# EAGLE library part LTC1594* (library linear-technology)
4-Channel, Micropower Sampling 12-Bit Serial I/O A/D Converter

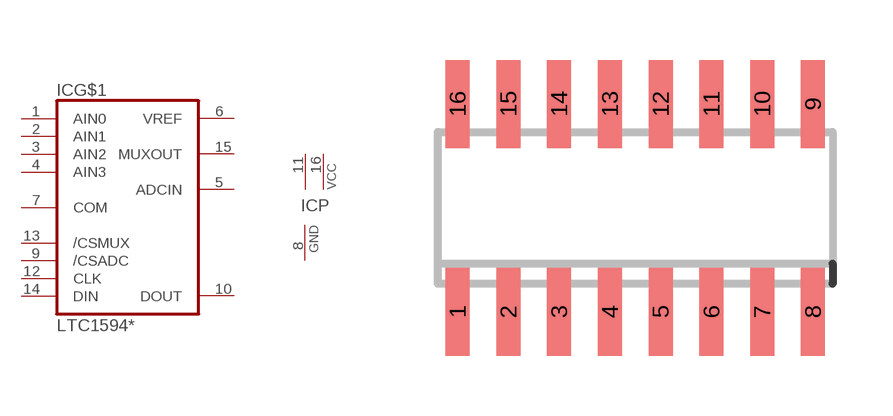
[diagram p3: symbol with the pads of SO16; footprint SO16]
Designator prefix IC; gates G$1=LTC1594 P=PWRN-CC-G

## LTC1594CS, LTC1594IS  [SO16]
1  G$1:AIN0  in
2  G$1:AIN1  in
3  G$1:AIN2  in
4  G$1:AIN3  in
5  G$1:ADCIN  in
6  G$1:VREF  in
7  G$1:COM  in
8  P:GND  pwr
9  G$1:/CSADC  in
10  G$1:DOUT  hiz
11  P:VCC  pwr
12  G$1:CLK  in
13  G$1:/CSMUX  in
14  G$1:DIN  in
15  G$1:MUXOUT  out
16  P:VCC  pwr

## Footprint SO16 (pad centres in mm)
smd 0.6 x 2.2: 1 -4.445,-2.6; 2 -3.175,-2.6; 3 -1.905,-2.6; 4 -0.635,-2.6; 5 0.635,-2.6; 6 1.905,-2.6; 7 3.175,-2.6; 8 4.445,-2.6; 9 4.445,2.6; 10 3.175,2.6; 11 1.905,2.6; 12 0.635,2.6; 13 -0.635,2.6; 14 -1.905,2.6; 15 -3.175,2.6; 16 -4.445,2.6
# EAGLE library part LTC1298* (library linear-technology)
Micropower, Sampling 12Bit A/D Converter Two Singleended Inputs

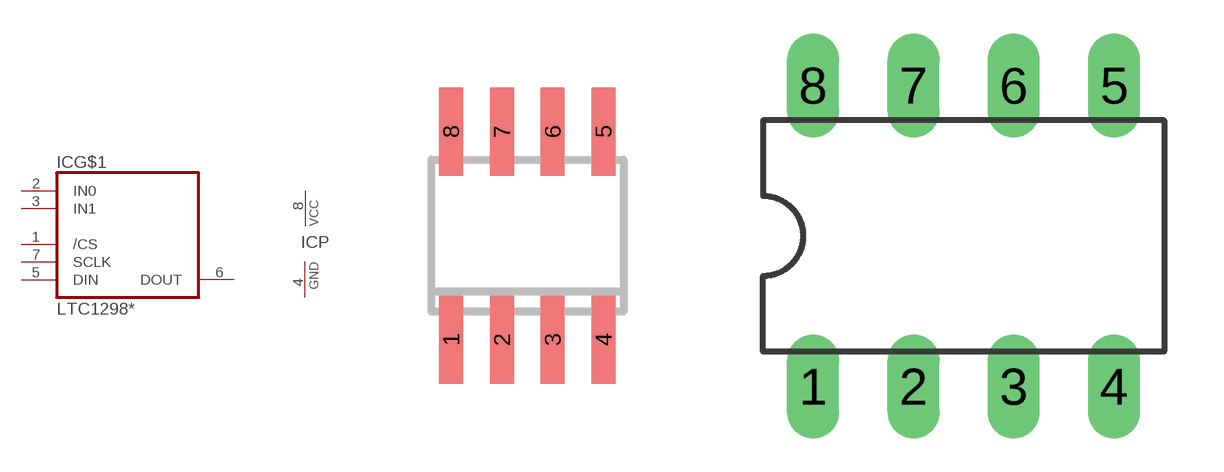
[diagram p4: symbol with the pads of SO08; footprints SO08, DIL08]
Designator prefix IC; gates G$1=LTC1298 P=PWRN-C-G

## LTC1298CS8, LTC1298IS8  [SO08]
1  G$1:/CS  in
2  G$1:IN0  in
3  G$1:IN1  in
4  P:GND  pwr
5  G$1:DIN  in
6  G$1:DOUT  hiz
7  G$1:SCLK  in
8  P:VCC  pwr

## LTC1298CN8, LTC1298IN8  [DIL08]
Pads as for SO08

## Footprint SO08 (pad centres in mm)
Small Outline IC
smd 0.6 x 2.2: 1 -1.905,-2.6; 2 -0.635,-2.6; 3 0.635,-2.6; 4 1.905,-2.6; 5 1.905,2.6; 6 0.635,2.6; 7 -0.635,2.6; 8 -1.905,2.6

## Footprint DIL08 (pad centres in mm)
Dual In Line Package
drill 0.813 long: 1 -3.81,-3.81; 2 -1.27,-3.81; 3 1.27,-3.81; 4 3.81,-3.81; 5 3.81,3.81; 6 1.27,3.81; 7 -1.27,3.81; 8 -3.81,3.81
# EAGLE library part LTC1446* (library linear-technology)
Dual 12-Bit Rail-to-Rail Micropower DACs

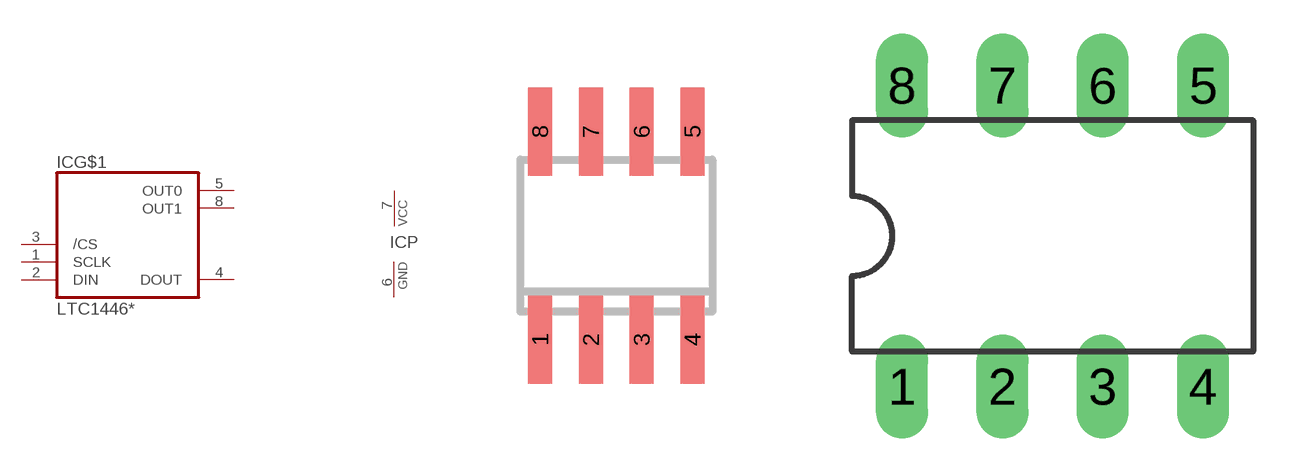
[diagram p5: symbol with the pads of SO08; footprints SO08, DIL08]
Designator prefix IC; gates G$1=LTC1446 P=PWRN-C-G

## LTC1446CS8, LTC1446IS8, LTC1446LCS8, LTC1446LIS8  [SO08]
1  G$1:SCLK  in
2  G$1:DIN  in
3  G$1:/CS  in
4  G$1:DOUT  hiz
5  G$1:OUT0  out
6  P:GND  pwr
7  P:VCC  pwr
8  G$1:OUT1  out

## LTC1446CN8, LTC1446IN8, LTC1446LCN8, LTC1446LIN8  [DIL08]
Pads as for SO08

## Footprint SO08 (pad centres in mm)
Small Outline IC
smd 0.6 x 2.2: 1 -1.905,-2.6; 2 -0.635,-2.6; 3 0.635,-2.6; 4 1.905,-2.6; 5 1.905,2.6; 6 0.635,2.6; 7 -0.635,2.6; 8 -1.905,2.6

## Footprint DIL08 (pad centres in mm)
Dual In Line Package
drill 0.813 long: 1 -3.81,-3.81; 2 -1.27,-3.81; 3 1.27,-3.81; 4 3.81,-3.81; 5 3.81,3.81; 6 1.27,3.81; 7 -1.27,3.81; 8 -3.81,3.81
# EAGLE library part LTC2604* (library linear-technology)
Quad 16-Bit Rail-to-Rail DACs

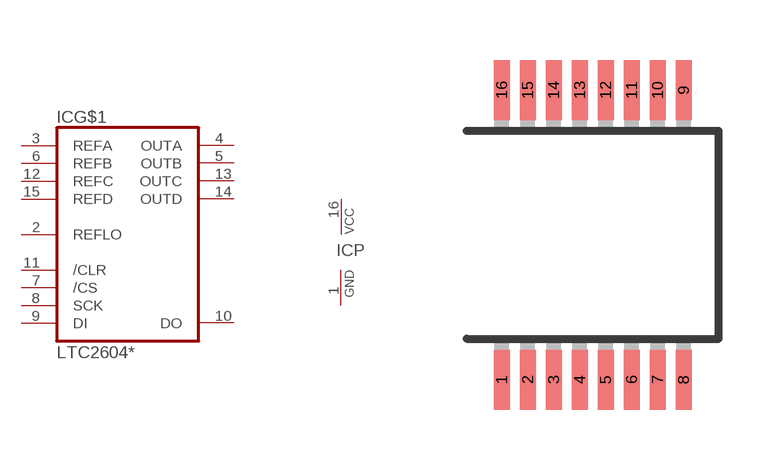
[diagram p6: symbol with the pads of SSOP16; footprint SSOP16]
Designator prefix IC; gates P=PWRN-C-G G$1=LTC2604

## LTC2604CGN, LTC2604IGN  [SSOP16]
1  P:GND  pwr
2  G$1:REFLO  pas
3  G$1:REFA  pas
4  G$1:OUTA  out
5  G$1:OUTB  out
6  G$1:REFB  pas
7  G$1:/CS  in
8  G$1:SCK  in
9  G$1:DI  in
10  G$1:DO  hiz
11  G$1:/CLR  in
12  G$1:REFC  pas
13  G$1:OUTC  out
14  G$1:OUTD  out
15  G$1:REFD  pas
16  P:VCC  pwr

## Footprint SSOP16 (pad centres in mm)
smd 0.4 x 1.5: 1 -2.275,-3.625; 2 -1.625,-3.625; 3 -0.975,-3.625; 4 -0.325,-3.625; 5 0.325,-3.625; 6 0.975,-3.625; 7 1.625,-3.625; 8 2.275,-3.625; 9 2.275,3.625; 10 1.625,3.625; 11 0.975,3.625; 12 0.325,3.625; 13 -0.325,3.625; 14 -0.975,3.625; 15 -1.625,3.625; 16 -2.275,3.625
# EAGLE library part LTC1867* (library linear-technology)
12-/16-Bit, 8-Channel 200ksps ADC

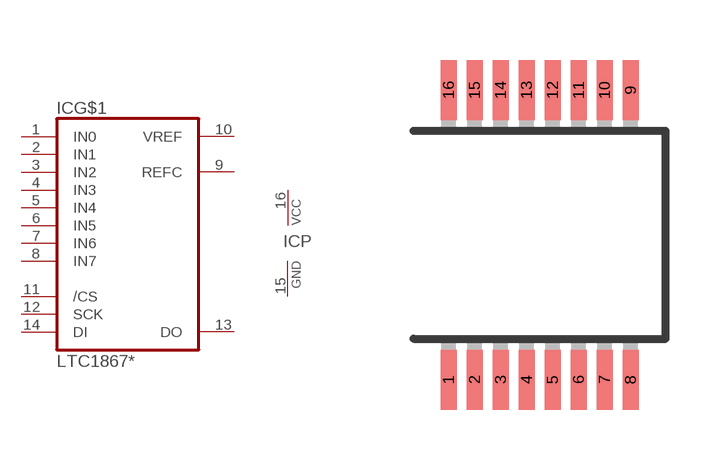
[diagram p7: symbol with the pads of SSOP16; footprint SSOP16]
Designator prefix IC; gates P=PWRN-C-G G$1=LTC1867

## LTC1867ACGN, LTC1867AIGN, LTC1867CGN, LTC1867IGN  [SSOP16]
1  G$1:IN0  in
2  G$1:IN1  in
3  G$1:IN2  in
4  G$1:IN3  in
5  G$1:IN4  in
6  G$1:IN5  in
7  G$1:IN6  in
8  G$1:IN7  in
9  G$1:REFC  pas
10  G$1:VREF  pas
11  G$1:/CS  in
12  G$1:SCK  in
13  G$1:DO  hiz
14  G$1:DI  in
15  P:GND  pwr
16  P:VCC  pwr

## Footprint SSOP16 (pad centres in mm)
smd 0.4 x 1.5: 1 -2.275,-3.625; 2 -1.625,-3.625; 3 -0.975,-3.625; 4 -0.325,-3.625; 5 0.325,-3.625; 6 0.975,-3.625; 7 1.625,-3.625; 8 2.275,-3.625; 9 2.275,3.625; 10 1.625,3.625; 11 0.975,3.625; 12 0.325,3.625; 13 -0.325,3.625; 14 -0.975,3.625; 15 -1.625,3.625; 16 -2.275,3.625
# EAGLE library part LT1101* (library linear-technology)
Precision, Micropower, Single Supply Instrumentation Amplifier (Fixed Gain A=10 or 100)

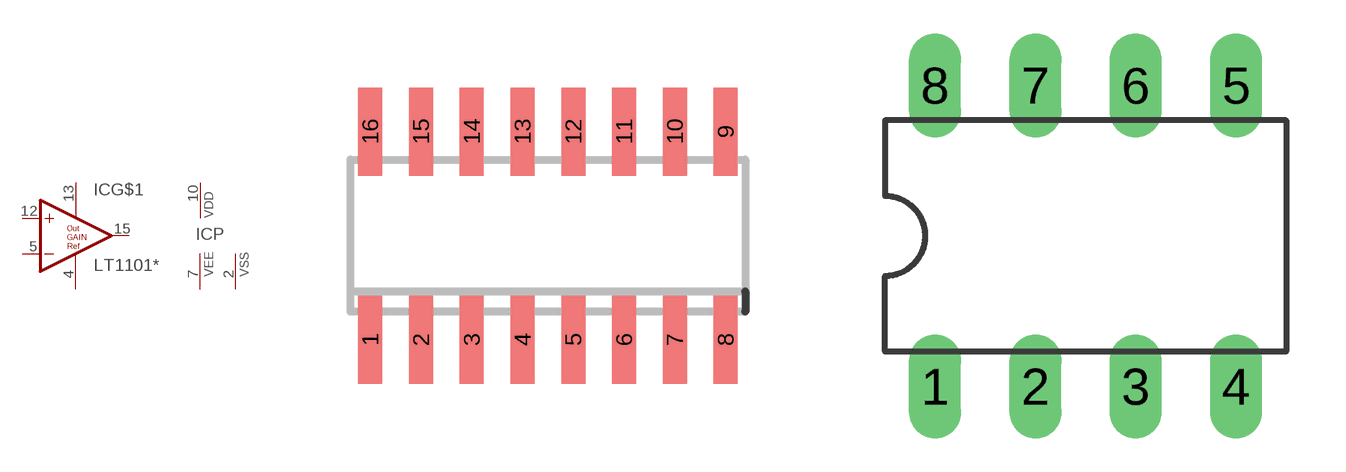
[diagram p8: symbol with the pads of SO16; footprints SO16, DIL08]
Designator prefix IC; gates G$1=LT1101 P=PWRN-D-E-S

## LT1101SW, LT1101ISW  [SO16]
2  P:VSS  pwr
4  G$1:GREF  pas
5  G$1:-IN  in
7  P:VEE  pwr
10  P:VDD  pwr
12  G$1:+IN  in
13  G$1:GOUT  pas
15  G$1:OUT  out

## LT1101ACN8, LT1101AIN8, LT1101CN8, LT1101IN8  [DIL08]
1  P:VSS  pwr
2  G$1:GREF  pas
3  G$1:-IN  in
4  P:VEE  pwr
5  P:VDD  pwr
6  G$1:+IN  in
7  G$1:GOUT  pas
8  G$1:OUT  out

## Footprint SO16 (pad centres in mm)
smd 0.6 x 2.2: 1 -4.445,-2.6; 2 -3.175,-2.6; 3 -1.905,-2.6; 4 -0.635,-2.6; 5 0.635,-2.6; 6 1.905,-2.6; 7 3.175,-2.6; 8 4.445,-2.6; 9 4.445,2.6; 10 3.175,2.6; 11 1.905,2.6; 12 0.635,2.6; 13 -0.635,2.6; 14 -1.905,2.6; 15 -3.175,2.6; 16 -4.445,2.6

## Footprint DIL08 (pad centres in mm)
Dual In Line Package
drill 0.813 long: 1 -3.81,-3.81; 2 -1.27,-3.81; 3 1.27,-3.81; 4 3.81,-3.81; 5 3.81,3.81; 6 1.27,3.81; 7 -1.27,3.81; 8 -3.81,3.81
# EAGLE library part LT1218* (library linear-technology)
Precision Rail-to-Rail Input and Output OpAmp with Shutdown Input

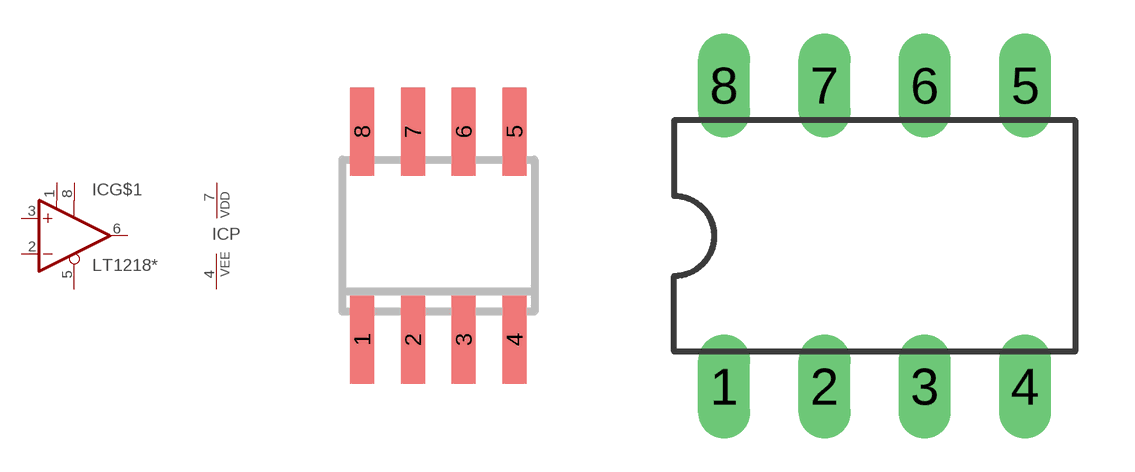
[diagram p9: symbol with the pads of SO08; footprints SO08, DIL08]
Designator prefix IC; gates G$1=LT1218 P=PWRN-D-E

## LT1218CS8, LT1218LCS8  [SO08]
1  G$1:TRIM1  pas
2  G$1:-IN  in
3  G$1:+IN  in
4  P:VEE  pwr
5  G$1:/SHDN  pas
6  G$1:OUT  out
7  P:VDD  pwr
8  G$1:TRIM2  pas

## LT1218CN8, LT1218LCN8  [DIL08]
Pads as for SO08

## Footprint SO08 (pad centres in mm)
Small Outline IC
smd 0.6 x 2.2: 1 -1.905,-2.6; 2 -0.635,-2.6; 3 0.635,-2.6; 4 1.905,-2.6; 5 1.905,2.6; 6 0.635,2.6; 7 -0.635,2.6; 8 -1.905,2.6

## Footprint DIL08 (pad centres in mm)
Dual In Line Package
drill 0.813 long: 1 -3.81,-3.81; 2 -1.27,-3.81; 3 1.27,-3.81; 4 3.81,-3.81; 5 3.81,3.81; 6 1.27,3.81; 7 -1.27,3.81; 8 -3.81,3.81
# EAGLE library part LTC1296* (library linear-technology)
Single Chip 12-Bit Data Acquisition System

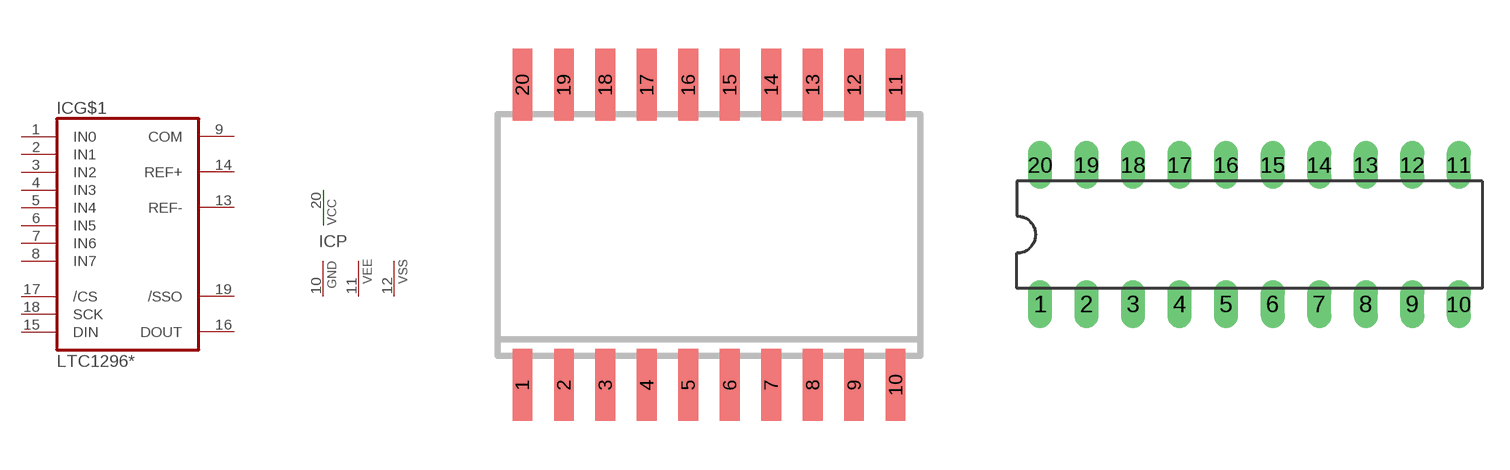
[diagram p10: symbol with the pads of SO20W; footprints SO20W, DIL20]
Designator prefix IC; gates G$1=LTC1296 P=PWRN-C-G-E-S

## LTC1296BCS, LTC1296CCS, LTC1296DCS  [SO20W]
1  G$1:IN0  in
2  G$1:IN1  in
3  G$1:IN2  in
4  G$1:IN3  in
5  G$1:IN4  in
6  G$1:IN5  in
7  G$1:IN6  in
8  G$1:IN7  in
9  G$1:COM  pas
10  P:GND  pwr
11  P:VEE  pwr
12  P:VSS  pwr
13  G$1:REF-  pas
14  G$1:REF+  pas
15  G$1:DIN  in
16  G$1:DOUT  hiz
17  G$1:/CS  in
18  G$1:SCK  in
19  G$1:/SSO  out
20  P:VCC  pwr

## LTC1296BCN, LTC1296BIN, LTC1296CCN, LTC1296CIN, LTC1296DCN, LTC1296DIN  [DIL20]
Pads as for SO20W

## Footprint SO20W (pad centres in mm)
smd 0.6 x 2.2: 1 -5.715,-4.6; 2 -4.445,-4.6; 3 -3.175,-4.6; 4 -1.905,-4.6; 5 -0.635,-4.6; 6 0.635,-4.6; 7 1.905,-4.6; 8 3.175,-4.6; 9 4.445,-4.6; 10 5.715,-4.6; 11 5.715,4.6; 12 4.445,4.6; 13 3.175,4.6; 14 1.905,4.6; 15 0.635,4.6; 16 -0.635,4.6; 17 -1.905,4.6; 18 -3.175,4.6; 19 -4.445,4.6; 20 -5.715,4.6

## Footprint DIL20 (pad centres in mm)
drill 0.813 long: 1 -11.43,-3.81; 2 -8.89,-3.81; 3 -6.35,-3.81; 4 -3.81,-3.81; 5 -1.27,-3.81; 6 1.27,-3.81; 7 3.81,-3.81; 8 6.35,-3.81; 9 8.89,-3.81; 10 11.43,-3.81; 11 11.43,3.81; 12 8.89,3.81; 13 6.35,3.81; 14 3.81,3.81; 15 1.27,3.81; 16 -1.27,3.81; 17 -3.81,3.81; 18 -6.35,3.81; 19 -8.89,3.81; 20 -11.43,3.81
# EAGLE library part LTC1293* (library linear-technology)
Single Chip 12-Bit Data Acquisition System

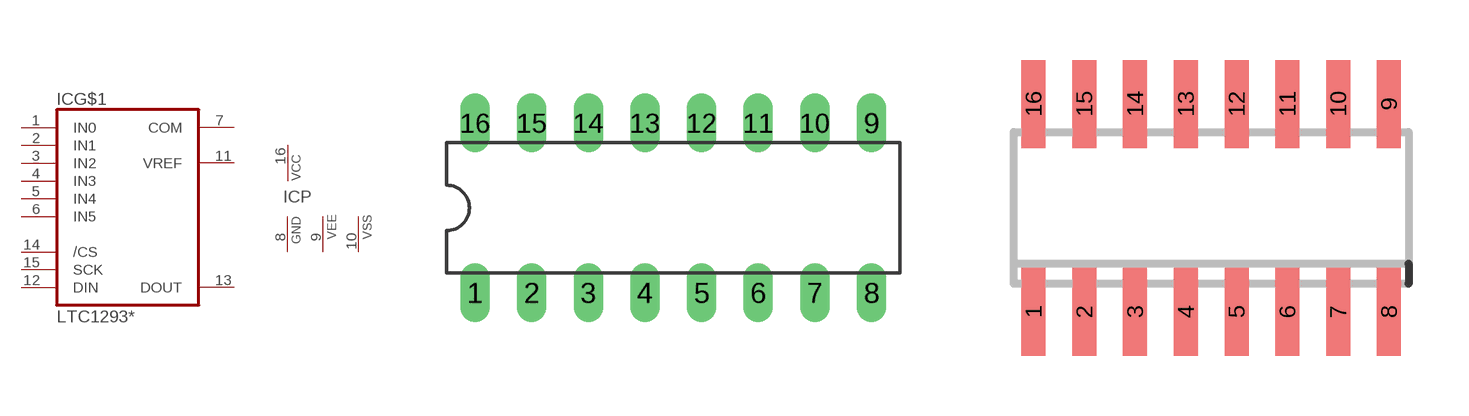
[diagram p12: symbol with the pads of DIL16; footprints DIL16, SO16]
Designator prefix IC; gates G$1=LTC1293 P=PWRN-C-G-E-S

## LTC1293BCN, LTC1293BIN, LTC1293CCN, LTC1293CIN, LTC1293DCN, LTC1293DIN  [DIL16]
1  G$1:IN0  in
2  G$1:IN1  in
3  G$1:IN2  in
4  G$1:IN3  in
5  G$1:IN4  in
6  G$1:IN5  in
7  G$1:COM  pas
8  P:GND  pwr
9  P:VEE  pwr
10  P:VSS  pwr
11  G$1:VREF  pas
12  G$1:DIN  in
13  G$1:DOUT  hiz
14  G$1:/CS  in
15  G$1:SCK  in
16  P:VCC  pwr

## LTC1293BCS, LTC1293CCS, LTC1293DCS  [SO16]
Pads as for DIL16

## Footprint DIL16 (pad centres in mm)
drill 0.813 long: 1 -8.89,-3.81; 2 -6.35,-3.81; 3 -3.81,-3.81; 4 -1.27,-3.81; 5 1.27,-3.81; 6 3.81,-3.81; 7 6.35,-3.81; 8 8.89,-3.81; 9 8.89,3.81; 10 6.35,3.81; 11 3.81,3.81; 12 1.27,3.81; 13 -1.27,3.81; 14 -3.81,3.81; 15 -6.35,3.81; 16 -8.89,3.81

## Footprint SO16 (pad centres in mm)
smd 0.6 x 2.2: 1 -4.445,-2.6; 2 -3.175,-2.6; 3 -1.905,-2.6; 4 -0.635,-2.6; 5 0.635,-2.6; 6 1.905,-2.6; 7 3.175,-2.6; 8 4.445,-2.6; 9 4.445,2.6; 10 3.175,2.6; 11 1.905,2.6; 12 0.635,2.6; 13 -0.635,2.6; 14 -1.905,2.6; 15 -3.175,2.6; 16 -4.445,2.6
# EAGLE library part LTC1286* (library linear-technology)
Micropower, Sampling 12Bit A/D Converter Differential Input

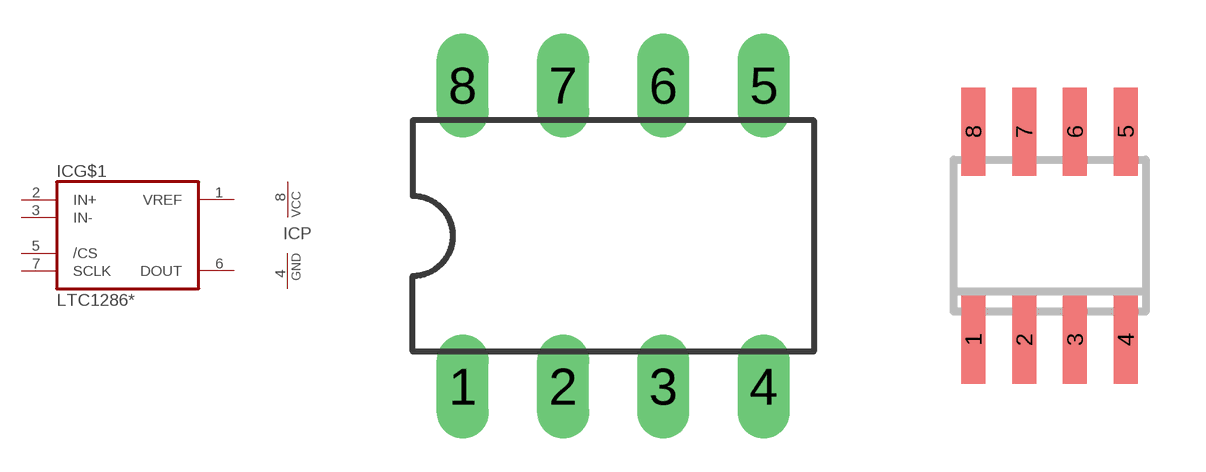
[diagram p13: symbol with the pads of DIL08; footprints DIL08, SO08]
Designator prefix IC; gates G$1=LTC1286 P=PWRN-C-G

## LTC1286CN8, LTC1286IN8  [DIL08]
1  G$1:VREF  pas
2  G$1:IN+  in
3  G$1:IN-  in
4  P:GND  pwr
5  G$1:/CS  in
6  G$1:DOUT  hiz
7  G$1:SCLK  in
8  P:VCC  pwr

## LTC1286CS8, LTC1286IS8  [SO08]
Pads as for DIL08

## Footprint DIL08 (pad centres in mm)
Dual In Line Package
drill 0.813 long: 1 -3.81,-3.81; 2 -1.27,-3.81; 3 1.27,-3.81; 4 3.81,-3.81; 5 3.81,3.81; 6 1.27,3.81; 7 -1.27,3.81; 8 -3.81,3.81

## Footprint SO08 (pad centres in mm)
Small Outline IC
smd 0.6 x 2.2: 1 -1.905,-2.6; 2 -0.635,-2.6; 3 0.635,-2.6; 4 1.905,-2.6; 5 1.905,2.6; 6 0.635,2.6; 7 -0.635,2.6; 8 -1.905,2.6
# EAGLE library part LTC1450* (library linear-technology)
Parallel Input, 12-Bit Rail-to-Rail Micropower DACs

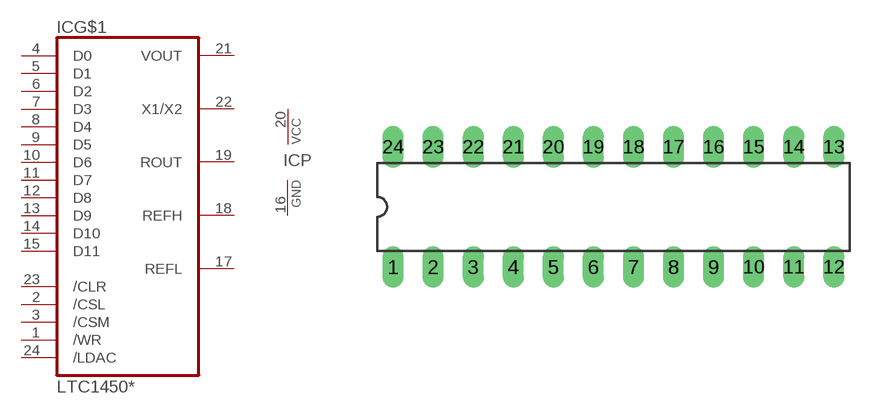
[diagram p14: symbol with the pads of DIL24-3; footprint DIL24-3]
Designator prefix IC; gates P=PWRN-C-G G$1=LTC1450

## LTC1450CN, LTC1450IN, LTC1450LCN, LTC1450LIN  [DIL24-3]
1  G$1:/WR  in
2  G$1:/CSL  in
3  G$1:/CSM  in
4  G$1:D0  in
5  G$1:D1  in
6  G$1:D2  in
7  G$1:D3  in
8  G$1:D4  in
9  G$1:D5  in
10  G$1:D6  in
11  G$1:D7  in
12  G$1:D8  in
13  G$1:D9  in
14  G$1:D10  in
15  G$1:D11  in
16  P:GND  pwr
17  G$1:REFL  pas
18  G$1:REFH  pas
19  G$1:ROUT  out
20  P:VCC  pwr
21  G$1:VOUT  out
22  G$1:X1/X2  pas
23  G$1:/CLR  in
24  G$1:/LDAC  in

## Footprint DIL24-3 (pad centres in mm)
drill 0.813 long: 1 -13.97,-3.81; 2 -11.43,-3.81; 3 -8.89,-3.81; 4 -6.35,-3.81; 5 -3.81,-3.81; 6 -1.27,-3.81; 7 1.27,-3.81; 8 3.81,-3.81; 9 6.35,-3.81; 10 8.89,-3.81; 11 11.43,-3.81; 12 13.97,-3.81; 13 13.97,3.81; 14 11.43,3.81; 15 8.89,3.81; 16 6.35,3.81; 17 3.81,3.81; 18 1.27,3.81; 19 -1.27,3.81; 20 -3.81,3.81; 21 -6.35,3.81; 22 -8.89,3.81; 23 -11.43,3.81; 24 -13.97,3.81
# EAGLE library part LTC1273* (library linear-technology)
12-Bit, 300ksps Sampling A/D Converters with Reference

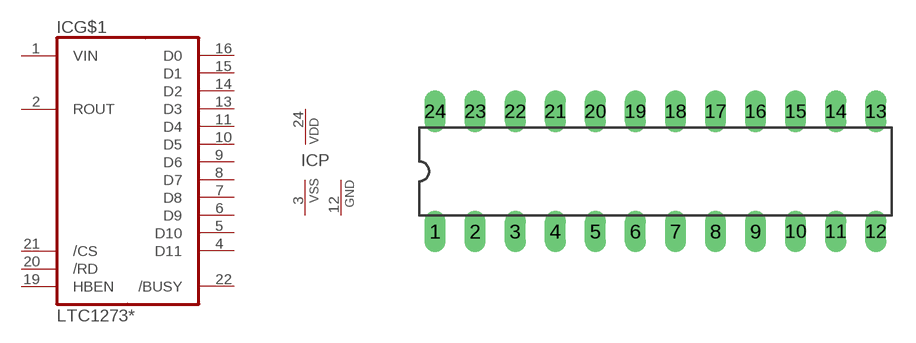
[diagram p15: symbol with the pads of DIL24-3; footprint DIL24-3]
Designator prefix IC; gates G$1=LTC1273 P=PWRN-D-S-G

## LTC1273ACN, LTC1273BCN  [DIL24-3]
1  G$1:VIN  in
2  G$1:ROUT  out
3  P:VSS  pwr
4  G$1:D11  hiz
5  G$1:D10  hiz
6  G$1:D9  hiz
7  G$1:D8  hiz
8  G$1:D7  hiz
9  G$1:D6  hiz
10  G$1:D5  hiz
11  G$1:D4  hiz
12  P:GND  pwr
13  G$1:D3  hiz
14  G$1:D2  hiz
15  G$1:D1  hiz
16  G$1:D0  hiz
19  G$1:HBEN  in
20  G$1:/RD  in
21  G$1:/CS  in
22  G$1:/BUSY  out
24  P:VDD  pwr

## Footprint DIL24-3 (pad centres in mm)
drill 0.813 long: 1 -13.97,-3.81; 2 -11.43,-3.81; 3 -8.89,-3.81; 4 -6.35,-3.81; 5 -3.81,-3.81; 6 -1.27,-3.81; 7 1.27,-3.81; 8 3.81,-3.81; 9 6.35,-3.81; 10 8.89,-3.81; 11 11.43,-3.81; 12 13.97,-3.81; 13 13.97,3.81; 14 11.43,3.81; 15 8.89,3.81; 16 6.35,3.81; 17 3.81,3.81; 18 1.27,3.81; 19 -1.27,3.81; 20 -3.81,3.81; 21 -6.35,3.81; 22 -8.89,3.81; 23 -11.43,3.81; 24 -13.97,3.81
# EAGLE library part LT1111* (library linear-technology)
Micropower DC/DC Converter Adjustable and Fixed 5V, 12V

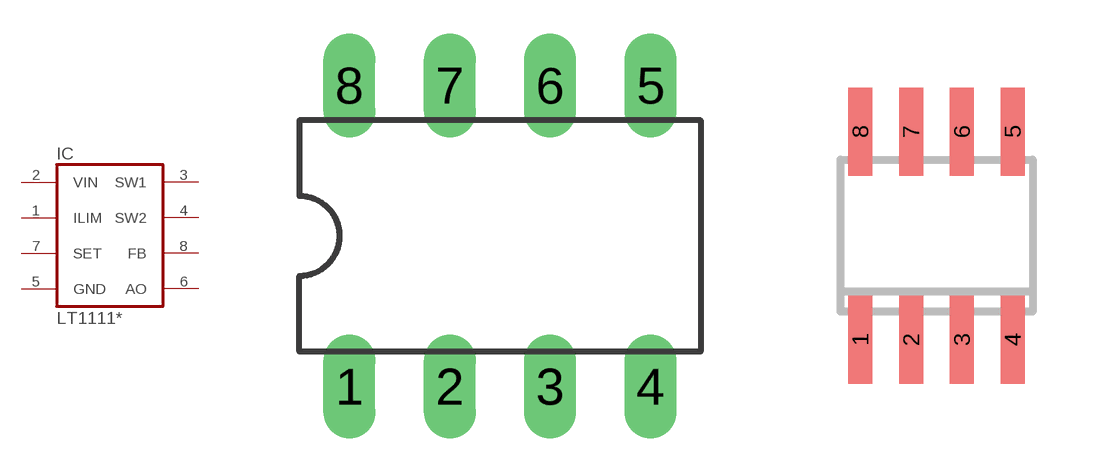
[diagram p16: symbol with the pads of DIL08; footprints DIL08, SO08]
Designator prefix IC

## LT1111CN8, LT1111IN8  [DIL08]
1  ILIM
2  VIN
3  SW1
4  SW2
5  GND
6  AO
7  SET
8  FB

## LT1111CS8, LT1111IS8  [SO08]
Pads as for DIL08

## Footprint DIL08 (pad centres in mm)
Dual In Line Package
drill 0.813 long: 1 -3.81,-3.81; 2 -1.27,-3.81; 3 1.27,-3.81; 4 3.81,-3.81; 5 3.81,3.81; 6 1.27,3.81; 7 -1.27,3.81; 8 -3.81,3.81

## Footprint SO08 (pad centres in mm)
Small Outline IC
smd 0.6 x 2.2: 1 -1.905,-2.6; 2 -0.635,-2.6; 3 0.635,-2.6; 4 1.905,-2.6; 5 1.905,2.6; 6 0.635,2.6; 7 -0.635,2.6; 8 -1.905,2.6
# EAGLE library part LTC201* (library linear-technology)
Micropower, Low Charge Injection, Quad CMOS Analog Switches

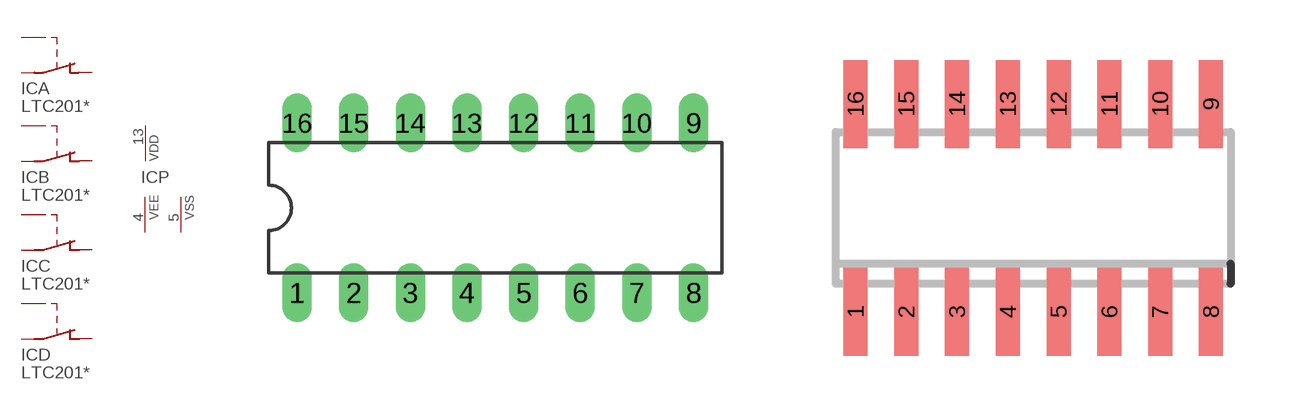
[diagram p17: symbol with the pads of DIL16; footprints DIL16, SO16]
Designator prefix IC; gates A=LTC203NC B=LTC203NC C=LTC203NC D=LTC203NC P=PWRN-D-E-S

## LTC201ACN  [DIL16]
1  A:IN  pas
2  A:D  pas
3  A:S  pas
4  P:VEE  pwr
5  P:VSS  pwr
6  D:S  pas
7  D:D  pas
8  D:IN  pas
9  C:IN  pas
10  C:D  pas
11  C:S  pas
13  P:VDD  pwr
14  B:S  pas
15  B:D  pas
16  B:IN  pas

## LTC201ACS  [SO16]
Pads as for DIL16

## Footprint DIL16 (pad centres in mm)
drill 0.813 long: 1 -8.89,-3.81; 2 -6.35,-3.81; 3 -3.81,-3.81; 4 -1.27,-3.81; 5 1.27,-3.81; 6 3.81,-3.81; 7 6.35,-3.81; 8 8.89,-3.81; 9 8.89,3.81; 10 6.35,3.81; 11 3.81,3.81; 12 1.27,3.81; 13 -1.27,3.81; 14 -3.81,3.81; 15 -6.35,3.81; 16 -8.89,3.81

## Footprint SO16 (pad centres in mm)
smd 0.6 x 2.2: 1 -4.445,-2.6; 2 -3.175,-2.6; 3 -1.905,-2.6; 4 -0.635,-2.6; 5 0.635,-2.6; 6 1.905,-2.6; 7 3.175,-2.6; 8 4.445,-2.6; 9 4.445,2.6; 10 3.175,2.6; 11 1.905,2.6; 12 0.635,2.6; 13 -0.635,2.6; 14 -1.905,2.6; 15 -3.175,2.6; 16 -4.445,2.6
